VERSION 5.7 ;
  NOWIREEXTENSIONATPIN ON ;
  DIVIDERCHAR "/" ;
  BUSBITCHARS "[]" ;
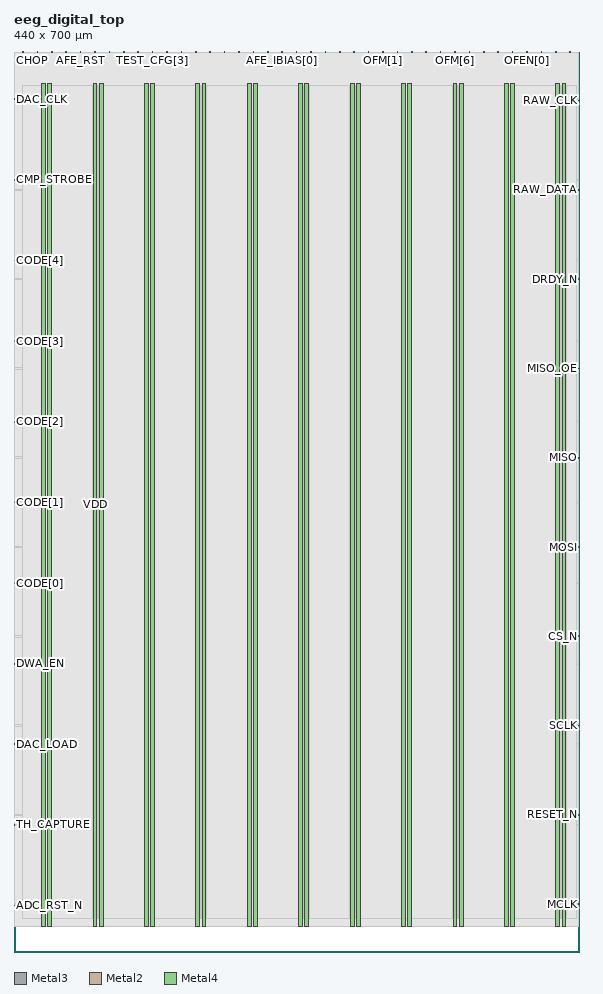
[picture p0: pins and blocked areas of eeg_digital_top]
MACRO eeg_digital_top
  CLASS BLOCK ;
  FOREIGN eeg_digital_top ;
  ORIGIN 0.000 0.000 ;
  SIZE 440.000 BY 700.000 ;
  PIN ADC_RST_N
    DIRECTION OUTPUT ;
    USE SIGNAL ;
    ANTENNADIFFAREA 1.386000 ;
    PORT
      LAYER Metal3 ;
        RECT 0.000 35.840 0.560 36.400 ;
    END
  END ADC_RST_N
  PIN AFE_IBIAS[0]
    DIRECTION OUTPUT ;
    USE SIGNAL ;
    ANTENNADIFFAREA 1.386000 ;
    PORT
      LAYER Metal2 ;
        RECT 208.320 699.440 208.880 700.000 ;
    END
  END AFE_IBIAS[0]
  PIN AFE_IBIAS[1]
    DIRECTION OUTPUT ;
    USE SIGNAL ;
    ANTENNADIFFAREA 1.386000 ;
    PORT
      LAYER Metal2 ;
        RECT 219.520 699.440 220.080 700.000 ;
    END
  END AFE_IBIAS[1]
  PIN AFE_RST
    DIRECTION OUTPUT ;
    USE SIGNAL ;
    ANTENNADIFFAREA 1.386000 ;
    PORT
      LAYER Metal2 ;
        RECT 51.520 699.440 52.080 700.000 ;
    END
  END AFE_RST
  PIN BTRIM_N[0]
    DIRECTION OUTPUT ;
    USE SIGNAL ;
    ANTENNADIFFAREA 1.386000 ;
    PORT
      LAYER Metal2 ;
        RECT 253.120 699.440 253.680 700.000 ;
    END
  END BTRIM_N[0]
  PIN BTRIM_N[1]
    DIRECTION OUTPUT ;
    USE SIGNAL ;
    ANTENNADIFFAREA 1.386000 ;
    PORT
      LAYER Metal2 ;
        RECT 264.320 699.440 264.880 700.000 ;
    END
  END BTRIM_N[1]
  PIN BTRIM_P[0]
    DIRECTION OUTPUT ;
    USE SIGNAL ;
    ANTENNADIFFAREA 1.386000 ;
    PORT
      LAYER Metal2 ;
        RECT 230.720 699.440 231.280 700.000 ;
    END
  END BTRIM_P[0]
  PIN BTRIM_P[1]
    DIRECTION OUTPUT ;
    USE SIGNAL ;
    ANTENNADIFFAREA 1.386000 ;
    PORT
      LAYER Metal2 ;
        RECT 241.920 699.440 242.480 700.000 ;
    END
  END BTRIM_P[1]
  PIN CHOP
    DIRECTION OUTPUT ;
    USE SIGNAL ;
    ANTENNADIFFAREA 1.386000 ;
    PORT
      LAYER Metal2 ;
        RECT 6.720 699.440 7.280 700.000 ;
    END
  END CHOP
  PIN CHOP1
    DIRECTION OUTPUT ;
    USE SIGNAL ;
    ANTENNADIFFAREA 1.386000 ;
    PORT
      LAYER Metal2 ;
        RECT 62.720 699.440 63.280 700.000 ;
    END
  END CHOP1
  PIN CHOP_BLANK
    DIRECTION OUTPUT ;
    USE SIGNAL ;
    ANTENNADIFFAREA 1.386000 ;
    PORT
      LAYER Metal2 ;
        RECT 29.120 699.440 29.680 700.000 ;
    END
  END CHOP_BLANK
  PIN CHOP_EN
    DIRECTION OUTPUT ;
    USE SIGNAL ;
    ANTENNADIFFAREA 1.386000 ;
    PORT
      LAYER Metal2 ;
        RECT 40.320 699.440 40.880 700.000 ;
    END
  END CHOP_EN
  PIN CHOP_OUT
    DIRECTION OUTPUT ;
    USE SIGNAL ;
    ANTENNADIFFAREA 1.386000 ;
    PORT
      LAYER Metal2 ;
        RECT 17.920 699.440 18.480 700.000 ;
    END
  END CHOP_OUT
  PIN CMP_STROBE
    DIRECTION OUTPUT ;
    USE SIGNAL ;
    ANTENNADIFFAREA 1.386000 ;
    PORT
      LAYER Metal3 ;
        RECT 0.000 600.320 0.560 600.880 ;
    END
  END CMP_STROBE
  PIN CODE[0]
    DIRECTION INPUT ;
    USE SIGNAL ;
    ANTENNAGATEAREA 1.353000 ;
    PORT
      LAYER Metal3 ;
        RECT 0.000 286.720 0.560 287.280 ;
    END
  END CODE[0]
  PIN CODE[1]
    DIRECTION INPUT ;
    USE SIGNAL ;
    ANTENNAGATEAREA 0.853500 ;
    PORT
      LAYER Metal3 ;
        RECT 0.000 349.440 0.560 350.000 ;
    END
  END CODE[1]
  PIN CODE[2]
    DIRECTION INPUT ;
    USE SIGNAL ;
    ANTENNAGATEAREA 0.853500 ;
    PORT
      LAYER Metal3 ;
        RECT 0.000 412.160 0.560 412.720 ;
    END
  END CODE[2]
  PIN CODE[3]
    DIRECTION INPUT ;
    USE SIGNAL ;
    ANTENNAGATEAREA 1.353000 ;
    PORT
      LAYER Metal3 ;
        RECT 0.000 474.880 0.560 475.440 ;
    END
  END CODE[3]
  PIN CODE[4]
    DIRECTION INPUT ;
    USE SIGNAL ;
    ANTENNAGATEAREA 1.353000 ;
    PORT
      LAYER Metal3 ;
        RECT 0.000 537.600 0.560 538.160 ;
    END
  END CODE[4]
  PIN CPF_TRIM[0]
    DIRECTION OUTPUT ;
    USE SIGNAL ;
    ANTENNADIFFAREA 1.386000 ;
    PORT
      LAYER Metal2 ;
        RECT 163.520 699.440 164.080 700.000 ;
    END
  END CPF_TRIM[0]
  PIN CPF_TRIM[1]
    DIRECTION OUTPUT ;
    USE SIGNAL ;
    ANTENNADIFFAREA 1.386000 ;
    PORT
      LAYER Metal2 ;
        RECT 174.720 699.440 175.280 700.000 ;
    END
  END CPF_TRIM[1]
  PIN CPF_TRIM[2]
    DIRECTION OUTPUT ;
    USE SIGNAL ;
    ANTENNADIFFAREA 1.386000 ;
    PORT
      LAYER Metal2 ;
        RECT 185.920 699.440 186.480 700.000 ;
    END
  END CPF_TRIM[2]
  PIN CPF_TRIM[3]
    DIRECTION OUTPUT ;
    USE SIGNAL ;
    ANTENNADIFFAREA 1.386000 ;
    PORT
      LAYER Metal2 ;
        RECT 197.120 699.440 197.680 700.000 ;
    END
  END CPF_TRIM[3]
  PIN CS_N
    DIRECTION INPUT ;
    USE SIGNAL ;
    ANTENNAGATEAREA 0.853500 ;
    PORT
      LAYER Metal3 ;
        RECT 439.440 245.280 440.000 245.840 ;
    END
  END CS_N
  PIN DAC_CLK
    DIRECTION OUTPUT ;
    USE SIGNAL ;
    ANTENNADIFFAREA 1.386000 ;
    PORT
      LAYER Metal3 ;
        RECT 0.000 663.040 0.560 663.600 ;
    END
  END DAC_CLK
  PIN DAC_LOAD
    DIRECTION OUTPUT ;
    USE SIGNAL ;
    ANTENNADIFFAREA 1.386000 ;
    PORT
      LAYER Metal3 ;
        RECT 0.000 161.280 0.560 161.840 ;
    END
  END DAC_LOAD
  PIN DRDY_N
    DIRECTION OUTPUT ;
    USE SIGNAL ;
    ANTENNADIFFAREA 1.386000 ;
    PORT
      LAYER Metal3 ;
        RECT 439.440 523.040 440.000 523.600 ;
    END
  END DRDY_N
  PIN DWA_EN
    DIRECTION OUTPUT ;
    USE SIGNAL ;
    ANTENNADIFFAREA 1.386000 ;
    PORT
      LAYER Metal3 ;
        RECT 0.000 224.000 0.560 224.560 ;
    END
  END DWA_EN
  PIN MCLK
    DIRECTION INPUT ;
    USE SIGNAL ;
    ANTENNAGATEAREA 10.823999 ;
    PORT
      LAYER Metal3 ;
        RECT 439.440 36.960 440.000 37.520 ;
    END
  END MCLK
  PIN MISO
    DIRECTION OUTPUT ;
    USE SIGNAL ;
    ANTENNADIFFAREA 1.386000 ;
    PORT
      LAYER Metal3 ;
        RECT 439.440 384.160 440.000 384.720 ;
    END
  END MISO
  PIN MISO_OE
    DIRECTION OUTPUT ;
    USE SIGNAL ;
    ANTENNADIFFAREA 1.386000 ;
    PORT
      LAYER Metal3 ;
        RECT 439.440 453.600 440.000 454.160 ;
    END
  END MISO_OE
  PIN MOSI
    DIRECTION INPUT ;
    USE SIGNAL ;
    ANTENNAGATEAREA 0.853500 ;
    PORT
      LAYER Metal3 ;
        RECT 439.440 314.720 440.000 315.280 ;
    END
  END MOSI
  PIN OFEN[0]
    DIRECTION OUTPUT ;
    USE SIGNAL ;
    ANTENNADIFFAREA 1.386000 ;
    PORT
      LAYER Metal2 ;
        RECT 398.720 699.440 399.280 700.000 ;
    END
  END OFEN[0]
  PIN OFEN[1]
    DIRECTION OUTPUT ;
    USE SIGNAL ;
    ANTENNADIFFAREA 1.386000 ;
    PORT
      LAYER Metal2 ;
        RECT 409.920 699.440 410.480 700.000 ;
    END
  END OFEN[1]
  PIN OFEN[2]
    DIRECTION OUTPUT ;
    USE SIGNAL ;
    ANTENNADIFFAREA 1.386000 ;
    PORT
      LAYER Metal2 ;
        RECT 421.120 699.440 421.680 700.000 ;
    END
  END OFEN[2]
  PIN OFEN[3]
    DIRECTION OUTPUT ;
    USE SIGNAL ;
    ANTENNADIFFAREA 1.386000 ;
    PORT
      LAYER Metal2 ;
        RECT 432.320 699.440 432.880 700.000 ;
    END
  END OFEN[3]
  PIN OFM[0]
    DIRECTION OUTPUT ;
    USE SIGNAL ;
    ANTENNADIFFAREA 1.386000 ;
    PORT
      LAYER Metal2 ;
        RECT 275.520 699.440 276.080 700.000 ;
    END
  END OFM[0]
  PIN OFM[1]
    DIRECTION OUTPUT ;
    USE SIGNAL ;
    ANTENNADIFFAREA 1.386000 ;
    PORT
      LAYER Metal2 ;
        RECT 286.720 699.440 287.280 700.000 ;
    END
  END OFM[1]
  PIN OFM[2]
    DIRECTION OUTPUT ;
    USE SIGNAL ;
    ANTENNADIFFAREA 1.386000 ;
    PORT
      LAYER Metal2 ;
        RECT 297.920 699.440 298.480 700.000 ;
    END
  END OFM[2]
  PIN OFM[3]
    DIRECTION OUTPUT ;
    USE SIGNAL ;
    ANTENNADIFFAREA 1.386000 ;
    PORT
      LAYER Metal2 ;
        RECT 309.120 699.440 309.680 700.000 ;
    END
  END OFM[3]
  PIN OFM[4]
    DIRECTION OUTPUT ;
    USE SIGNAL ;
    ANTENNADIFFAREA 1.386000 ;
    PORT
      LAYER Metal2 ;
        RECT 320.320 699.440 320.880 700.000 ;
    END
  END OFM[4]
  PIN OFM[5]
    DIRECTION OUTPUT ;
    USE SIGNAL ;
    ANTENNADIFFAREA 1.386000 ;
    PORT
      LAYER Metal2 ;
        RECT 331.520 699.440 332.080 700.000 ;
    END
  END OFM[5]
  PIN OFM[6]
    DIRECTION OUTPUT ;
    USE SIGNAL ;
    ANTENNADIFFAREA 1.386000 ;
    PORT
      LAYER Metal2 ;
        RECT 342.720 699.440 343.280 700.000 ;
    END
  END OFM[6]
  PIN OFM[7]
    DIRECTION OUTPUT ;
    USE SIGNAL ;
    ANTENNADIFFAREA 1.386000 ;
    PORT
      LAYER Metal2 ;
        RECT 353.920 699.440 354.480 700.000 ;
    END
  END OFM[7]
  PIN OFM[8]
    DIRECTION OUTPUT ;
    USE SIGNAL ;
    ANTENNADIFFAREA 1.386000 ;
    PORT
      LAYER Metal2 ;
        RECT 365.120 699.440 365.680 700.000 ;
    END
  END OFM[8]
  PIN OFM[9]
    DIRECTION OUTPUT ;
    USE SIGNAL ;
    ANTENNADIFFAREA 1.386000 ;
    PORT
      LAYER Metal2 ;
        RECT 376.320 699.440 376.880 700.000 ;
    END
  END OFM[9]
  PIN OFS
    DIRECTION OUTPUT ;
    USE SIGNAL ;
    ANTENNADIFFAREA 1.386000 ;
    PORT
      LAYER Metal2 ;
        RECT 387.520 699.440 388.080 700.000 ;
    END
  END OFS
  PIN RAW_CLK
    DIRECTION OUTPUT ;
    USE SIGNAL ;
    ANTENNADIFFAREA 1.386000 ;
    PORT
      LAYER Metal3 ;
        RECT 439.440 661.920 440.000 662.480 ;
    END
  END RAW_CLK
  PIN RAW_DATA
    DIRECTION OUTPUT ;
    USE SIGNAL ;
    ANTENNADIFFAREA 1.386000 ;
    PORT
      LAYER Metal3 ;
        RECT 439.440 592.480 440.000 593.040 ;
    END
  END RAW_DATA
  PIN RESET_N
    DIRECTION INPUT ;
    USE SIGNAL ;
    ANTENNAGATEAREA 0.853500 ;
    PORT
      LAYER Metal3 ;
        RECT 439.440 106.400 440.000 106.960 ;
    END
  END RESET_N
  PIN SCLK
    DIRECTION INPUT ;
    USE SIGNAL ;
    ANTENNAGATEAREA 0.853500 ;
    PORT
      LAYER Metal3 ;
        RECT 439.440 175.840 440.000 176.400 ;
    END
  END SCLK
  PIN TEST_CFG[0]
    DIRECTION OUTPUT ;
    USE SIGNAL ;
    ANTENNADIFFAREA 1.386000 ;
    PORT
      LAYER Metal2 ;
        RECT 73.920 699.440 74.480 700.000 ;
    END
  END TEST_CFG[0]
  PIN TEST_CFG[1]
    DIRECTION OUTPUT ;
    USE SIGNAL ;
    ANTENNADIFFAREA 1.386000 ;
    PORT
      LAYER Metal2 ;
        RECT 85.120 699.440 85.680 700.000 ;
    END
  END TEST_CFG[1]
  PIN TEST_CFG[2]
    DIRECTION OUTPUT ;
    USE SIGNAL ;
    ANTENNADIFFAREA 1.386000 ;
    PORT
      LAYER Metal2 ;
        RECT 96.320 699.440 96.880 700.000 ;
    END
  END TEST_CFG[2]
  PIN TEST_CFG[3]
    DIRECTION OUTPUT ;
    USE SIGNAL ;
    ANTENNADIFFAREA 1.386000 ;
    PORT
      LAYER Metal2 ;
        RECT 107.520 699.440 108.080 700.000 ;
    END
  END TEST_CFG[3]
  PIN TEST_CFG[4]
    DIRECTION OUTPUT ;
    USE SIGNAL ;
    ANTENNADIFFAREA 1.386000 ;
    PORT
      LAYER Metal2 ;
        RECT 118.720 699.440 119.280 700.000 ;
    END
  END TEST_CFG[4]
  PIN TEST_CFG[5]
    DIRECTION OUTPUT ;
    USE SIGNAL ;
    ANTENNADIFFAREA 1.386000 ;
    PORT
      LAYER Metal2 ;
        RECT 129.920 699.440 130.480 700.000 ;
    END
  END TEST_CFG[5]
  PIN TEST_CFG[6]
    DIRECTION OUTPUT ;
    USE SIGNAL ;
    ANTENNADIFFAREA 1.386000 ;
    PORT
      LAYER Metal2 ;
        RECT 141.120 699.440 141.680 700.000 ;
    END
  END TEST_CFG[6]
  PIN TEST_CFG[7]
    DIRECTION OUTPUT ;
    USE SIGNAL ;
    ANTENNADIFFAREA 1.386000 ;
    PORT
      LAYER Metal2 ;
        RECT 152.320 699.440 152.880 700.000 ;
    END
  END TEST_CFG[7]
  PIN TH_CAPTURE
    DIRECTION OUTPUT ;
    USE SIGNAL ;
    ANTENNADIFFAREA 1.386000 ;
    PORT
      LAYER Metal3 ;
        RECT 0.000 98.560 0.560 99.120 ;
    END
  END TH_CAPTURE
  PIN VDD
    DIRECTION INOUT ;
    USE POWER ;
    PORT
      LAYER Metal4 ;
        RECT 21.540 19.860 24.540 675.660 ;
    END
    PORT
      LAYER Metal4 ;
        RECT 61.540 19.860 64.540 675.660 ;
    END
    PORT
      LAYER Metal4 ;
        RECT 101.540 19.860 104.540 675.660 ;
    END
    PORT
      LAYER Metal4 ;
        RECT 141.540 19.860 144.540 675.660 ;
    END
    PORT
      LAYER Metal4 ;
        RECT 181.540 19.860 184.540 675.660 ;
    END
    PORT
      LAYER Metal4 ;
        RECT 221.540 19.860 224.540 675.660 ;
    END
    PORT
      LAYER Metal4 ;
        RECT 261.540 19.860 264.540 675.660 ;
    END
    PORT
      LAYER Metal4 ;
        RECT 301.540 19.860 304.540 675.660 ;
    END
    PORT
      LAYER Metal4 ;
        RECT 341.540 19.860 344.540 675.660 ;
    END
    PORT
      LAYER Metal4 ;
        RECT 381.540 19.860 384.540 675.660 ;
    END
    PORT
      LAYER Metal4 ;
        RECT 421.540 19.860 424.540 675.660 ;
    END
  END VDD
  PIN VSS
    DIRECTION INOUT ;
    USE GROUND ;
    PORT
      LAYER Metal4 ;
        RECT 26.240 19.860 29.240 675.660 ;
    END
    PORT
      LAYER Metal4 ;
        RECT 66.240 19.860 69.240 675.660 ;
    END
    PORT
      LAYER Metal4 ;
        RECT 106.240 19.860 109.240 675.660 ;
    END
    PORT
      LAYER Metal4 ;
        RECT 146.240 19.860 149.240 675.660 ;
    END
    PORT
      LAYER Metal4 ;
        RECT 186.240 19.860 189.240 675.660 ;
    END
    PORT
      LAYER Metal4 ;
        RECT 226.240 19.860 229.240 675.660 ;
    END
    PORT
      LAYER Metal4 ;
        RECT 266.240 19.860 269.240 675.660 ;
    END
    PORT
      LAYER Metal4 ;
        RECT 306.240 19.860 309.240 675.660 ;
    END
    PORT
      LAYER Metal4 ;
        RECT 346.240 19.860 349.240 675.660 ;
    END
    PORT
      LAYER Metal4 ;
        RECT 386.240 19.860 389.240 675.660 ;
    END
    PORT
      LAYER Metal4 ;
        RECT 426.240 19.860 429.240 675.660 ;
    END
  END VSS
  OBS
      LAYER Nwell ;
        RECT 3.790 19.730 435.810 675.790 ;
      LAYER Metal1 ;
        RECT 6.720 19.710 432.880 675.810 ;
      LAYER Metal2 ;
        RECT 4.060 699.140 6.420 699.860 ;
        RECT 7.580 699.140 17.620 699.860 ;
        RECT 18.780 699.140 28.820 699.860 ;
        RECT 29.980 699.140 40.020 699.860 ;
        RECT 41.180 699.140 51.220 699.860 ;
        RECT 52.380 699.140 62.420 699.860 ;
        RECT 63.580 699.140 73.620 699.860 ;
        RECT 74.780 699.140 84.820 699.860 ;
        RECT 85.980 699.140 96.020 699.860 ;
        RECT 97.180 699.140 107.220 699.860 ;
        RECT 108.380 699.140 118.420 699.860 ;
        RECT 119.580 699.140 129.620 699.860 ;
        RECT 130.780 699.140 140.820 699.860 ;
        RECT 141.980 699.140 152.020 699.860 ;
        RECT 153.180 699.140 163.220 699.860 ;
        RECT 164.380 699.140 174.420 699.860 ;
        RECT 175.580 699.140 185.620 699.860 ;
        RECT 186.780 699.140 196.820 699.860 ;
        RECT 197.980 699.140 208.020 699.860 ;
        RECT 209.180 699.140 219.220 699.860 ;
        RECT 220.380 699.140 230.420 699.860 ;
        RECT 231.580 699.140 241.620 699.860 ;
        RECT 242.780 699.140 252.820 699.860 ;
        RECT 253.980 699.140 264.020 699.860 ;
        RECT 265.180 699.140 275.220 699.860 ;
        RECT 276.380 699.140 286.420 699.860 ;
        RECT 287.580 699.140 297.620 699.860 ;
        RECT 298.780 699.140 308.820 699.860 ;
        RECT 309.980 699.140 320.020 699.860 ;
        RECT 321.180 699.140 331.220 699.860 ;
        RECT 332.380 699.140 342.420 699.860 ;
        RECT 343.580 699.140 353.620 699.860 ;
        RECT 354.780 699.140 364.820 699.860 ;
        RECT 365.980 699.140 376.020 699.860 ;
        RECT 377.180 699.140 387.220 699.860 ;
        RECT 388.380 699.140 398.420 699.860 ;
        RECT 399.580 699.140 409.620 699.860 ;
        RECT 410.780 699.140 420.820 699.860 ;
        RECT 421.980 699.140 432.020 699.860 ;
        RECT 433.180 699.140 433.300 699.860 ;
        RECT 4.060 19.970 433.300 699.140 ;
      LAYER Metal3 ;
        RECT 0.560 663.900 439.440 699.300 ;
        RECT 0.860 662.780 439.440 663.900 ;
        RECT 0.860 662.740 439.140 662.780 ;
        RECT 0.560 661.620 439.140 662.740 ;
        RECT 0.560 601.180 439.440 661.620 ;
        RECT 0.860 600.020 439.440 601.180 ;
        RECT 0.560 593.340 439.440 600.020 ;
        RECT 0.560 592.180 439.140 593.340 ;
        RECT 0.560 538.460 439.440 592.180 ;
        RECT 0.860 537.300 439.440 538.460 ;
        RECT 0.560 523.900 439.440 537.300 ;
        RECT 0.560 522.740 439.140 523.900 ;
        RECT 0.560 475.740 439.440 522.740 ;
        RECT 0.860 474.580 439.440 475.740 ;
        RECT 0.560 454.460 439.440 474.580 ;
        RECT 0.560 453.300 439.140 454.460 ;
        RECT 0.560 413.020 439.440 453.300 ;
        RECT 0.860 411.860 439.440 413.020 ;
        RECT 0.560 385.020 439.440 411.860 ;
        RECT 0.560 383.860 439.140 385.020 ;
        RECT 0.560 350.300 439.440 383.860 ;
        RECT 0.860 349.140 439.440 350.300 ;
        RECT 0.560 315.580 439.440 349.140 ;
        RECT 0.560 314.420 439.140 315.580 ;
        RECT 0.560 287.580 439.440 314.420 ;
        RECT 0.860 286.420 439.440 287.580 ;
        RECT 0.560 246.140 439.440 286.420 ;
        RECT 0.560 244.980 439.140 246.140 ;
        RECT 0.560 224.860 439.440 244.980 ;
        RECT 0.860 223.700 439.440 224.860 ;
        RECT 0.560 176.700 439.440 223.700 ;
        RECT 0.560 175.540 439.140 176.700 ;
        RECT 0.560 162.140 439.440 175.540 ;
        RECT 0.860 160.980 439.440 162.140 ;
        RECT 0.560 107.260 439.440 160.980 ;
        RECT 0.560 106.100 439.140 107.260 ;
        RECT 0.560 99.420 439.440 106.100 ;
        RECT 0.860 98.260 439.440 99.420 ;
        RECT 0.560 37.820 439.440 98.260 ;
        RECT 0.560 36.700 439.140 37.820 ;
        RECT 0.860 36.660 439.140 36.700 ;
        RECT 0.860 35.540 439.440 36.660 ;
        RECT 0.560 20.020 439.440 35.540 ;
      LAYER Metal4 ;
        RECT 6.860 26.410 21.240 674.150 ;
        RECT 24.840 26.410 25.940 674.150 ;
        RECT 29.540 26.410 61.240 674.150 ;
        RECT 64.840 26.410 65.940 674.150 ;
        RECT 69.540 26.410 101.240 674.150 ;
        RECT 104.840 26.410 105.940 674.150 ;
        RECT 109.540 26.410 141.240 674.150 ;
        RECT 144.840 26.410 145.940 674.150 ;
        RECT 149.540 26.410 181.240 674.150 ;
        RECT 184.840 26.410 185.940 674.150 ;
        RECT 189.540 26.410 221.240 674.150 ;
        RECT 224.840 26.410 225.940 674.150 ;
        RECT 229.540 26.410 261.240 674.150 ;
        RECT 264.840 26.410 265.940 674.150 ;
        RECT 269.540 26.410 301.240 674.150 ;
        RECT 304.840 26.410 305.940 674.150 ;
        RECT 309.540 26.410 341.240 674.150 ;
        RECT 344.840 26.410 345.940 674.150 ;
        RECT 349.540 26.410 381.240 674.150 ;
        RECT 384.840 26.410 385.940 674.150 ;
        RECT 389.540 26.410 421.240 674.150 ;
        RECT 424.840 26.410 425.940 674.150 ;
        RECT 429.540 26.410 437.780 674.150 ;
  END
END eeg_digital_top
END LIBRARY

